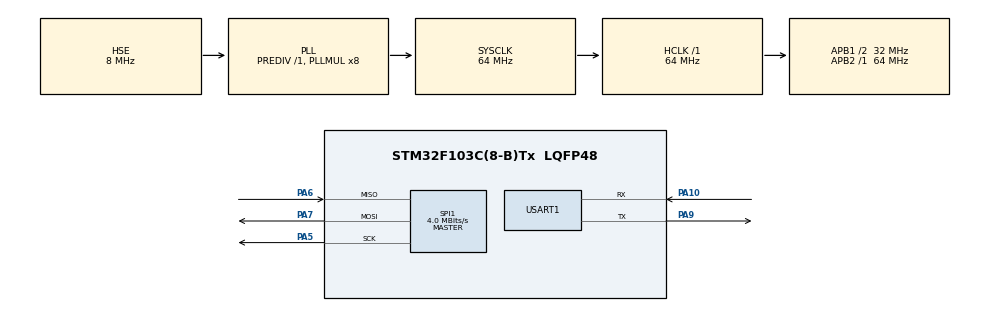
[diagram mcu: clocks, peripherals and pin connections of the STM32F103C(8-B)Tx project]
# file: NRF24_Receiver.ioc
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Mcu.Family=STM32F1
Mcu.Name=STM32F103C(8-B)Tx
Mcu.Package=LQFP48
NVIC.PriorityGroup=NVIC_PRIORITYGROUP_4
PA10.Mode=Asynchronous
PA10.Signal=USART1_RX
PA13.Mode=Serial_Wire
PA13.Signal=SYS_JTMS-SWDIO
PA14.Mode=Serial_Wire
PA14.Signal=SYS_JTCK-SWCLK
PA5.Mode=Full_Duplex_Master
PA5.Signal=SPI1_SCK
PA6.Mode=Full_Duplex_Master
PA6.Signal=SPI1_MISO
PA7.Mode=Full_Duplex_Master
PA7.Signal=SPI1_MOSI
PA9.Mode=Asynchronous
PA9.Signal=USART1_TX
PD0-OSC_IN.Mode=HSE-External-Oscillator
PD0-OSC_IN.Signal=RCC_OSC_IN
PD1-OSC_OUT.Mode=HSE-External-Oscillator
PD1-OSC_OUT.Signal=RCC_OSC_OUT
ProjectManager.HeapSize=0x200
ProjectManager.StackSize=0x400
ProjectManager.TargetToolchain=MDK-ARM V5
RCC.AHBFreq_Value=64000000
RCC.APB1CLKDivider=RCC_HCLK_DIV2
RCC.APB1Freq_Value=32000000
RCC.APB1TimFreq_Value=64000000
RCC.APB2Freq_Value=64000000
RCC.APB2TimFreq_Value=64000000
RCC.HCLKFreq_Value=64000000
RCC.PLLMUL=RCC_PLL_MUL8
RCC.PLLSourceVirtual=RCC_PLLSOURCE_HSE
RCC.SYSCLKFreq_VALUE=64000000
RCC.SYSCLKSource=RCC_SYSCLKSOURCE_PLLCLK
RCC.USBFreq_Value=64000000
SPI1.BaudRatePrescaler=SPI_BAUDRATEPRESCALER_16
SPI1.CalculateBaudRate=4.0 MBits/s
SPI1.Direction=SPI_DIRECTION_2LINES
SPI1.Mode=SPI_MODE_MASTER
SPI1.VirtualType=VM_MASTER
USART1.VirtualMode=VM_ASYNC
board=custom

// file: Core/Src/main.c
/**
  ******************************************************************************
  * @file           : main.c
  * @brief          : Main program body
  ******************************************************************************
  * @attention
  *
  * <h2><center>&copy; Copyright (c) 2022 STMicroelectronics.
  * All rights reserved.</center></h2>
  *
  * This software component is licensed by ST under BSD 3-Clause license,
  * the "License"; You may not use this file except in compliance with the
  * License. You may obtain a copy of the License at:
  *                        opensource.org/licenses/BSD-3-Clause
  *
  ******************************************************************************
  */
#include "main.h"
#include "stm32f1xx_hal.h"
#include "NRF24.h"
#include <string.h>

SPI_HandleTypeDef hspi1;
UART_HandleTypeDef huart1;

char str1[20]={0};
uint8_t *buf1;

void SystemClock_Config(void);
static void MX_GPIO_Init(void);
static void MX_SPI1_Init(void);
static void MX_USART1_UART_Init(void);

int main(void)
{
  uint8_t dt_reg=0, status=0x00;

  HAL_Init();

  SystemClock_Config();
  /* Initialize all configured peripherals */
  MX_GPIO_Init();
  MX_SPI1_Init();
  MX_USART1_UART_Init();

	NRF24_ini();    // инициализация модуля
  /* Infinite loop */

  while (1)
  {
    HAL_Delay(1000);

		buf1 = NRF24L01_Receive();
		sprintf(str1,"Received! Data: 0x%02X 0x%02X\r\n",buf1[0], buf1[1]);
		HAL_UART_Transmit(&huart1,(uint8_t*)str1,strlen(str1),0x1000);
		//NRF24_WriteReg(STATUS, 0x70); //TX_DS==0x20

		dt_reg = NRF24_ReadReg(CONFIG);
		sprintf(str1,"CONFIG: 0x%02X\r\n",dt_reg);
		HAL_UART_Transmit(&huart1,(uint8_t*)str1,strlen(str1),0x1000);

		dt_reg = NRF24_ReadReg(EN_AA);
		sprintf(str1,"EN_AA: 0x%02X\r\n",dt_reg);
		HAL_UART_Transmit(&huart1,(uint8_t*)str1,strlen(str1),0x1000);

		dt_reg = NRF24_ReadReg(EN_RXADDR);
		sprintf(str1,"EN_RXADDR: 0x%02X\r\n",dt_reg);
		HAL_UART_Transmit(&huart1,(uint8_t*)str1,strlen(str1),0x1000);

		dt_reg = NRF24_ReadReg(SETUP_AW);
		sprintf(str1,"SETUP_AW: 0x%02X\r\n",dt_reg);
		HAL_UART_Transmit(&huart1,(uint8_t*)str1,strlen(str1),0x1000);

		dt_reg = NRF24_ReadReg(SETUP_RETR);
		sprintf(str1,"SETUP_RETR: 0x%02X\r\n",dt_reg);
		HAL_UART_Transmit(&huart1,(uint8_t*)str1,strlen(str1),0x1000);

		dt_reg = NRF24_ReadReg(FEATURE);
		sprintf(str1,"FEATURE: 0x%02X\r\n",dt_reg);
		HAL_UART_Transmit(&huart1,(uint8_t*)str1,strlen(str1),0x1000);

		dt_reg = NRF24_ReadReg(DYNPD);
		sprintf(str1,"DYNPD: 0x%02X\r\n",dt_reg);
		HAL_UART_Transmit(&huart1,(uint8_t*)str1,strlen(str1),0x1000);

		dt_reg = NRF24_ReadReg(STATUS);
		sprintf(str1,"STATUS: 0x%02X\r\n",dt_reg);
		HAL_UART_Transmit(&huart1,(uint8_t*)str1,strlen(str1),0x1000);

		dt_reg = NRF24_ReadReg(RF_CH);
		sprintf(str1,"RF_CH: 0x%02X\r\n",dt_reg);
		HAL_UART_Transmit(&huart1,(uint8_t*)str1,strlen(str1),0x1000);

		dt_reg = NRF24_ReadReg(RF_SETUP);
		sprintf(str1,"RF_SETUP: 0x%02X\r\n",dt_reg);
		HAL_UART_Transmit(&huart1,(uint8_t*)str1,strlen(str1),0x1000);

		NRF24_Read_Buf(TX_ADDR,buf1,5);
		sprintf(str1,"TX_ADDR: 0x%02X, 0x%02X, 0x%02X, 0x%02X, 0x%02X\r\n",buf1[0],buf1[1],buf1[2],buf1[3],buf1[4]);
		HAL_UART_Transmit(&huart1,(uint8_t*)str1,strlen(str1),0x1000);

		NRF24_Read_Buf(RX_ADDR_P0,buf1,5);
		sprintf(str1,"RX_ADDR: 0x%02X, 0x%02X, 0x%02X, 0x%02X, 0x%02X\r\n",buf1[0],buf1[1],buf1[2],buf1[3],buf1[4]);
		HAL_UART_Transmit(&huart1,(uint8_t*)str1,strlen(str1),0x1000);

		sprintf(str1,"------------\r\n");
		HAL_UART_Transmit(&huart1,(uint8_t*)str1,strlen(str1),0x1000);
  }

}

void SystemClock_Config(void)
{
  RCC_OscInitTypeDef RCC_OscInitStruct = {0};
  RCC_ClkInitTypeDef RCC_ClkInitStruct = {0};

  /** Initializes the RCC Oscillators according to the specified parameters
  * in the RCC_OscInitTypeDef structure.
  */
  RCC_OscInitStruct.OscillatorType = RCC_OSCILLATORTYPE_HSE;
  RCC_OscInitStruct.HSEState = RCC_HSE_ON;
  RCC_OscInitStruct.HSEPredivValue = RCC_HSE_PREDIV_DIV1;
  RCC_OscInitStruct.HSIState = RCC_HSI_ON;
  RCC_OscInitStruct.PLL.PLLState = RCC_PLL_ON;
  RCC_OscInitStruct.PLL.PLLSource = RCC_PLLSOURCE_HSE;
  RCC_OscInitStruct.PLL.PLLMUL = RCC_PLL_MUL8;
  if (HAL_RCC_OscConfig(&RCC_OscInitStruct) != HAL_OK)
  {
    Error_Handler();
  }
  /** Initializes the CPU, AHB and APB buses clocks
  */
  RCC_ClkInitStruct.ClockType = RCC_CLOCKTYPE_HCLK|RCC_CLOCKTYPE_SYSCLK
                              |RCC_CLOCKTYPE_PCLK1|RCC_CLOCKTYPE_PCLK2;
  RCC_ClkInitStruct.SYSCLKSource = RCC_SYSCLKSOURCE_PLLCLK;
  RCC_ClkInitStruct.AHBCLKDivider = RCC_SYSCLK_DIV1;
  RCC_ClkInitStruct.APB1CLKDivider = RCC_HCLK_DIV2;
  RCC_ClkInitStruct.APB2CLKDivider = RCC_HCLK_DIV1;

  if (HAL_RCC_ClockConfig(&RCC_ClkInitStruct, FLASH_LATENCY_2) != HAL_OK)
  {
    Error_Handler();
  }
}

static void MX_SPI1_Init(void)
{

  /* SPI1 parameter configuration*/
  hspi1.Instance = SPI1;
  hspi1.Init.Mode = SPI_MODE_MASTER;
  hspi1.Init.Direction = SPI_DIRECTION_2LINES;
  hspi1.Init.DataSize = SPI_DATASIZE_8BIT;
  hspi1.Init.CLKPolarity = SPI_POLARITY_LOW;
  hspi1.Init.CLKPhase = SPI_PHASE_1EDGE;
  hspi1.Init.NSS = SPI_NSS_SOFT;
  hspi1.Init.BaudRatePrescaler = SPI_BAUDRATEPRESCALER_32;
  hspi1.Init.FirstBit = SPI_FIRSTBIT_MSB;
  hspi1.Init.TIMode = SPI_TIMODE_DISABLE;
  hspi1.Init.CRCCalculation = SPI_CRCCALCULATION_DISABLE;
  hspi1.Init.CRCPolynomial = 10;
  if (HAL_SPI_Init(&hspi1) != HAL_OK)
  {
    Error_Handler();
  }

}

static void MX_USART1_UART_Init(void)
{
  huart1.Instance = USART1;
  huart1.Init.BaudRate = 115200;
  huart1.Init.WordLength = UART_WORDLENGTH_8B;
  huart1.Init.StopBits = UART_STOPBITS_1;
  huart1.Init.Parity = UART_PARITY_NONE;
  huart1.Init.Mode = UART_MODE_TX_RX;
  huart1.Init.HwFlowCtl = UART_HWCONTROL_NONE;
  huart1.Init.OverSampling = UART_OVERSAMPLING_16;
  if (HAL_UART_Init(&huart1) != HAL_OK)
  {
    Error_Handler();
  }

}

static void MX_GPIO_Init(void)
{
  GPIO_InitTypeDef GPIO_InitStruct = {0};

  /* GPIO Ports Clock Enable */
  __HAL_RCC_GPIOC_CLK_ENABLE();
  __HAL_RCC_GPIOD_CLK_ENABLE();
  __HAL_RCC_GPIOA_CLK_ENABLE();

  /*Configure GPIO pin Output Level */
  HAL_GPIO_WritePin(LED_output_GPIO_Port, LED_output_Pin, GPIO_PIN_RESET);

  /*Configure GPIO pin Output Level */
  HAL_GPIO_WritePin(GPIOA, CE_output_Pin|CSN_output_Pin, GPIO_PIN_RESET);

  /*Configure GPIO pin : LED_output_Pin */
  GPIO_InitStruct.Pin = LED_output_Pin;
  GPIO_InitStruct.Mode = GPIO_MODE_OUTPUT_PP;
  GPIO_InitStruct.Pull = GPIO_NOPULL;
  GPIO_InitStruct.Speed = GPIO_SPEED_FREQ_LOW;
  HAL_GPIO_Init(LED_output_GPIO_Port, &GPIO_InitStruct);

  /*Configure GPIO pins : CE_output_Pin CSN_output_Pin */
  GPIO_InitStruct.Pin = CE_output_Pin|CSN_output_Pin;
  GPIO_InitStruct.Mode = GPIO_MODE_OUTPUT_PP;
  GPIO_InitStruct.Pull = GPIO_NOPULL;
  GPIO_InitStruct.Speed = GPIO_SPEED_FREQ_LOW;
  HAL_GPIO_Init(GPIOA, &GPIO_InitStruct);

}

void Error_Handler(void)
{
}

/************************ (C) COPYRIGHT STMicroelectronics *****END OF FILE****/
